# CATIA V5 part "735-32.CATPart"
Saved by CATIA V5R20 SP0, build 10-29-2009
Part number: 735-32
Bounding box of the stored display mesh (mm): x -28 to 28, y -28 to 28, z -30 to 45
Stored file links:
  C:\Users\Utente\Desktop\IO LAVORO\3D X SITO CF\X SITO\735\735-32.CATPart

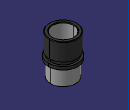
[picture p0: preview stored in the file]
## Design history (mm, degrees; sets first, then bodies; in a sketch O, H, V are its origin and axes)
Set1
  DatumSurface1 to DatumSurface25 "735-32"
Body1 (main body)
